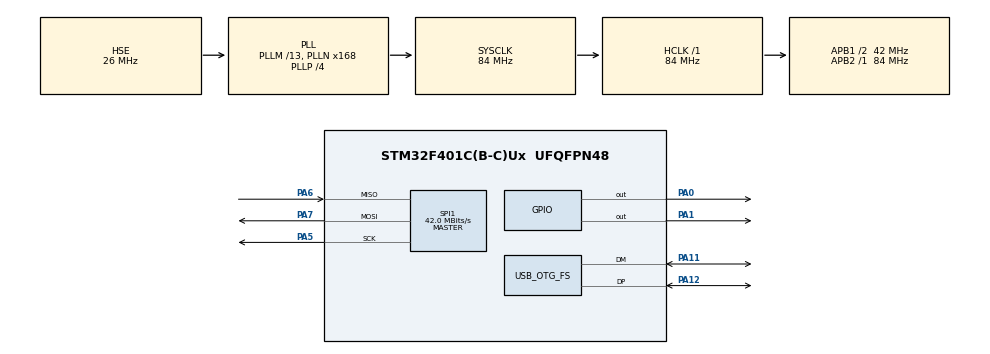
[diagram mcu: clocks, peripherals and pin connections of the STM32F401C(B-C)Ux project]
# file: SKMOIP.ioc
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Mcu.Family=STM32F4
Mcu.Name=STM32F401C(B-C)Ux
Mcu.Package=UFQFPN48
NVIC.OTG_FS_IRQn=true\:0\:0\:false\:false\:true\:false\:true\:true
NVIC.PriorityGroup=NVIC_PRIORITYGROUP_4
PA0-WKUP.Signal=GPIO_Output
PA1.Signal=GPIO_Output
PA11.Mode=Device_Only
PA11.Signal=USB_OTG_FS_DM
PA12.Mode=Device_Only
PA12.Signal=USB_OTG_FS_DP
PA13.Mode=Serial_Wire
PA13.Signal=SYS_JTMS-SWDIO
PA14.Mode=Serial_Wire
PA14.Signal=SYS_JTCK-SWCLK
PA5.Mode=Full_Duplex_Master
PA5.Signal=SPI1_SCK
PA6.Mode=Full_Duplex_Master
PA6.Signal=SPI1_MISO
PA7.Mode=Full_Duplex_Master
PA7.Signal=SPI1_MOSI
PH0\ -\ OSC_IN.Mode=HSE-External-Oscillator
PH0\ -\ OSC_IN.Signal=RCC_OSC_IN
PH1\ -\ OSC_OUT.Mode=HSE-External-Oscillator
PH1\ -\ OSC_OUT.Signal=RCC_OSC_OUT
ProjectManager.HeapSize=0x200
ProjectManager.StackSize=0x400
ProjectManager.TargetToolchain=STM32CubeIDE
RCC.48MHZClocksFreq_Value=48000000
RCC.AHBFreq_Value=84000000
RCC.APB1CLKDivider=RCC_HCLK_DIV2
RCC.APB1Freq_Value=42000000
RCC.APB1TimFreq_Value=84000000
RCC.APB2Freq_Value=84000000
RCC.APB2TimFreq_Value=84000000
RCC.CortexFreq_Value=84000000
RCC.HCLKFreq_Value=84000000
RCC.HSE_VALUE=26000000
RCC.HSI_VALUE=16000000
RCC.LSE_VALUE=32768
RCC.PLLM=13
RCC.PLLN=168
RCC.PLLP=RCC_PLLP_DIV4
RCC.PLLQ=7
RCC.SYSCLKFreq_VALUE=84000000
RCC.SYSCLKSource=RCC_SYSCLKSOURCE_PLLCLK
RCC.VCOOutputFreq_Value=336000000
SPI1.BaudRatePrescaler=SPI_BAUDRATEPRESCALER_2
SPI1.CalculateBaudRate=42.0 MBits/s
SPI1.Direction=SPI_DIRECTION_2LINES
SPI1.Mode=SPI_MODE_MASTER
SPI1.VirtualType=VM_MASTER
USB_DEVICE.CLASS_NAME_FS=HID
USB_DEVICE.VirtualMode=Hid
USB_DEVICE.VirtualModeFS=Hid_FS
USB_OTG_FS.VirtualMode=Device_Only
VP_USB_DEVICE_VS_USB_DEVICE_HID_FS.Mode=HID_FS
board=custom

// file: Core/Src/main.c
/* USER CODE BEGIN Header */
/**
  ******************************************************************************
  * @file           : main.c
  * @brief          : Main program body
  ******************************************************************************
  * @attention
  *
  * Copyright (c) 2023 STMicroelectronics.
  * All rights reserved.
  *
  * This software is licensed under terms that can be found in the LICENSE file
  * in the root directory of this software component.
  * If no LICENSE file comes with this software, it is provided AS-IS.
  *
  ******************************************************************************
  */
/* USER CODE END Header */
#include "main.h"
#include "usb_device.h"
#include "usbd_hid.h"
#include "w5500_spi.h"
#include "wizchip_conf.h"
#include "w5500.h"
#include "socket.h"
#include <stdbool.h>

/* USER CODE BEGIN PTD */

typedef uint8_t u8;
typedef int16_t s16;

/* 12 Bytes */
typedef struct NetworkPacket
{
	/* 1 Byte */
	u8 deviceType;

	union
	{
		/* Keyboard: 3 Bytes */
		struct
		{
			u8 keyStatus;
			u8 usbHIDUsageID;
			u8 modifierKeys;
		};

		/* Mouse: 9 Bytes */
		struct
		{
			/* BIT8(0) = left button is being pressed
			 * BIT8(1) = right button is being pressed
			 * BIT8(2) = middle button is being pressed */
			u8 mouseButtons;
			/* 8 Bytes */
			s16 mousePointX;
			s16 mousePointY;
			s16 mouseWheelX;
			s16 mouseWheelY;
		};

		/* Front Panel: 1 Byte */
		struct
		{
			u8 buttonStatus : 1;
			u8 isPowerButton : 1;
			u8 isResetButton : 1;
		};
	};
} NetworkPacket;

#define RECEIVE_BUFFER_SIZE (1 * sizeof(NetworkPacket)) // must be greater than or equal to 3
#define SEND_KEYBOARD_REPORT_INTERVAL 5
#define SEND_MOUSE_REPORT_INTERVAL 4
#define POWER_STATUS_READ_DELAY 500
#define FRONT_PANEL_POWER_PIN GPIO_PIN_0
#define FRONT_PANEL_RESET_PIN GPIO_PIN_1
#define FRONT_PANEL_POWER_LED_PIN GPIO_PIN_2

typedef enum input_type_t
{
	INPUT_TYPE_KEYBOARD = 0x00,
	INPUT_TYPE_MOUSE = 0x01,
} input_type_t;

typedef enum keycode_t
{
	KEYCODE_A = 4,
	KEYCODE_B,
	KEYCODE_C,
	KEYCODE_D,
	KEYCODE_E,
	KEYCODE_F,
	KEYCODE_G,
	KEYCODE_H,
	KEYCODE_I,
	KEYCODE_J,
	KEYCODE_K,
	KEYCODE_L,
	KEYCODE_M,
	KEYCODE_N,
	KEYCODE_O,
	KEYCODE_P,
	KEYCODE_Q,
	KEYCODE_R,
	KEYCODE_S,
	KEYCODE_T,
	KEYCODE_U,
	KEYCODE_V,
	KEYCODE_W,
	KEYCODE_X,
	KEYCODE_Y,
	KEYCODE_Z,
	KEYCODE_1,
	KEYCODE_2,
	KEYCODE_3,
	KEYCODE_4,
	KEYCODE_5,
	KEYCODE_6,
	KEYCODE_7,
	KEYCODE_8,
	KEYCODE_9,
	KEYCODE_0,
	KEYCODE_RETURN,
	KEYCODE_ESCAPE,
	KEYCODE_DELETEDOT,
	KEYCODE_TAB,
	KEYCODE_SPACEBAR,
	KEYCODE_MINUS,
	KEYCODE_EQUAL,
	KEYCODE_BRACKETSTART,
	KEYCODE_BRACKETEND,
	KEYCODE_BACKSLASH,
	KEYCODE_TILDE,
	KEYCODE_SEMICOLON,
	KEYCODE_SINGLEQUOTE,
	KEYCODE_TILDE2,
	KEYCODE_COMMA,
	KEYCODE_FULLSTOP,
	KEYCODE_FORWARDSLASH,
	KEYCODE_CAPSLOCK,
	KEYCODE_F1,
	KEYCODE_F2,
	KEYCODE_F3,
	KEYCODE_F4,
	KEYCODE_F5,
	KEYCODE_F6,
	KEYCODE_F7,
	KEYCODE_F8,
	KEYCODE_F9,
	KEYCODE_F10,
	KEYCODE_F11,
	KEYCODE_F12,
	KEYCODE_PRINTSCREEN,
	KEYCODE_SCROLLLOCK,
	KEYCODE_PAUSE,
	KEYCODE_INSERT,
	KEYCODE_HOME,
	KEYCODE_PAGEUP,
	KEYCODE_DELETE,
	KEYCODE_END,
	KEYCODE_PAGEDOWN,
	KEYCODE_RIGHTARROW,
	KEYCODE_LEFTARROW,
	KEYCODE_UPARROW,
	KEYCODE_KEYPADNUMLOCK,
	KEYCODE_KEYPADFORWARDSLASH,
	KEYCODE_KEYPADPLUS,
	KEYCODE_KEYPADMINUS,
	KEYCODE_KEYPADENTER,
	KEYCODE_KEYPAD1END,
	KEYCODE_KEYPAD2DOWNARROW,
	KEYCODE_KEYPAD3PAGEDOWN,
	KEYCODE_KEYPAD4LEFTARROW,
	KEYCODE_KEYPAD5,
	KEYCODE_KEYPAD6RIGHTARROW,
	KEYCODE_KEYPAD7HOME,
	KEYCODE_KEYPAD8UPARROW,
	KEYCODE_KEYPAD9PAGEUP,
	KEYCODE_KEYPAD0INSERT,
	KEYCODE_KEYPADDOTDELETE,
	KEYCODE_BACKSLASHBAR,
	KEYCODE_APPLICATION,
	KEYCODE_POWER,
	KEYCODE_KEYPADEQUAL,
	KEYCODE_MAX
} keycode_t;
/* USER CODE END PTD */

SPI_HandleTypeDef hspi1;
extern USBD_HandleTypeDef hUsbDeviceFS;

void SystemClock_Config(void);
static void MX_GPIO_Init(void);
static void MX_SPI1_Init(void);

/* USER CODE BEGIN 0 */

static wiz_NetInfo netInfo =
{
		.mac = { 0xec, 0xec, 0xec, 0xec, 0xec, 0xec },
		.ip = { 192, 168, 1, 117 },
		.sn  = { 255, 255, 255, 0 },
		.gw = { 192, 168, 1, 1 },
		.dns = { 0, 0, 0, 0 },
		.dhcp = NETINFO_STATIC
};

static uint8_t getKeyCodeFromASCII(char ch)
{
	switch(ch)
	{
	case 'a': return KEYCODE_A;
	case 'b': return KEYCODE_B;
	case 'c': return KEYCODE_C;
	case 'd': return KEYCODE_D;
	case 'e': return KEYCODE_E;
	case 'f': return KEYCODE_F;
	case 'g': return KEYCODE_G;
	case 'h': return KEYCODE_H;
	case 'i': return KEYCODE_I;
	case 'j': return KEYCODE_J;
	case 'k': return KEYCODE_K;
	case 'l': return KEYCODE_L;
	case 'm': return KEYCODE_M;
	case 'n': return KEYCODE_N;
	case 'o': return KEYCODE_O;
	case 'p': return KEYCODE_P;
	case 'q': return KEYCODE_Q;
	case 'r': return KEYCODE_R;
	case 's': return KEYCODE_S;
	case 't': return KEYCODE_T;
	case 'u': return KEYCODE_U;
	case 'v': return KEYCODE_V;
	case 'w': return KEYCODE_W;
	case 'x': return KEYCODE_X;
	case 'y': return KEYCODE_Y;
	case 'z': return KEYCODE_Z;
	case '1': return KEYCODE_1;
	case '2': return KEYCODE_2;
	case '3': return KEYCODE_3;
	case '4': return KEYCODE_4;
	case '5': return KEYCODE_5;
	case '6': return KEYCODE_6;
	case '7': return KEYCODE_7;
	case '8': return KEYCODE_8;
	case '9': return KEYCODE_9;
	case '0': return KEYCODE_0;
	case '\n': return KEYCODE_RETURN;
	case '\r': return KEYCODE_RETURN;
	case '\b': return KEYCODE_DELETEDOT;
	case '\t': return KEYCODE_TAB;
	case ' ': return KEYCODE_SPACEBAR;
	default: return 0;
	}
	return 0;
}

static void SetupNetworkDevice()
{
	wizchip_setnetinfo(&netInfo);
	ctlnetwork(CN_SET_NETINFO, &netInfo);
}

static char getCode(int32_t size)
{
	switch(size)
	{
	case SOCKERR_SOCKSTATUS: return 'd';
	case SOCKERR_SOCKMODE: return 'e';
	case SOCKERR_SOCKNUM: return 'f';
	case SOCKERR_DATALEN: return 'g';
	case SOCK_BUSY: return 'h';
	default: return 'i';
	}
}

struct
{
	  uint8_t reportID;
	  uint8_t modifier;
	  uint8_t reserved;
	  uint8_t keycode0;
	  uint8_t keycode1;
	  uint8_t keycode2;
	  uint8_t keycode3;
	  uint8_t keycode4;
	  uint8_t keycode5;
} keyboardReport = { 0x01 };

struct
{
	  uint8_t reportID;
	  uint8_t button;
	  int8_t mouse_x;
	  int8_t mouse_y;
	  int8_t wheel;
} mouseReport = { 0x02 };

typedef enum key_status_t
{
	KEY_STATUS_RELEASED = 0,
	KEY_STATUS_PRESSED
} key_status_t;

static inline void SendKeyboardReportASCII(uint8_t keycode)
{
	keyboardReport.keycode0 = getKeyCodeFromASCII((char)keycode);
	USBD_HID_SendReport(&hUsbDeviceFS, (uint8_t*)&keyboardReport, sizeof(keyboardReport));
	keyboardReport.keycode0 = 0;
	HAL_Delay(10);
	USBD_HID_SendReport(&hUsbDeviceFS, (uint8_t*)&keyboardReport, sizeof(keyboardReport));
	HAL_Delay(20);
}

static __attribute__((always_inline)) inline void SendKeyboardReport(uint8_t hidUsageID, uint8_t modifierKeys, key_status_t status)
{
	keyboardReport.modifier = modifierKeys;
	switch(status)
	{
		case KEY_STATUS_RELEASED:
			{
				keyboardReport.keycode0 = 0;
				break;
			}
		case KEY_STATUS_PRESSED:
			{
				keyboardReport.keycode0 = hidUsageID;
				break;
			}
		default: { return; }
	}
	USBD_HID_SendReport(&hUsbDeviceFS, (uint8_t*)&keyboardReport, sizeof(keyboardReport));
}

static __attribute__((always_inline)) inline void SendMouseReport(uint8_t button, int8_t dx, int8_t dy, int8_t wheel)
{
	mouseReport.button = button;
	mouseReport.mouse_x = dx;
	mouseReport.mouse_y = dy;
	mouseReport.wheel = wheel;
	USBD_HID_SendReport(&hUsbDeviceFS, (uint8_t*)&mouseReport, sizeof(mouseReport));
}

static inline void Info(const char* str)
{
	uint8_t len = strlen(str);
	for(uint8_t i = 0; i < len; i++)
		 SendKeyboardReportASCII(str[i]);
}

static inline void Error(const char* str)
{
	Info("Error: ");
	Info(str);
	while(1);
}

/* USER CODE END 0 */

int main(void)
{

  /* MCU Configuration--------------------------------------------------------*/

  /* Reset of all peripherals, Initializes the Flash interface and the Systick. */
  HAL_Init();

  /* Configure the system clock */
  SystemClock_Config();

  /* Initialize all configured peripherals */
  MX_GPIO_Init();
  MX_SPI1_Init();
  MX_USB_DEVICE_Init();
  /* USER CODE BEGIN 2 */
CREATE_SOCKET:
  W5500_Init();
  SetupNetworkDevice();
  SOCKET mySocket = socket(0, Sn_MR_TCP, 2000, 0);

  if(mySocket != 0)
  {
	  Error("failed to create socket 0\n");
  }

  if(sizeof(NetworkPacket) != 12)
  {
  	Error("sizeof network packet incorrect");
  }

  uint8_t recieveBuffer[RECEIVE_BUFFER_SIZE];

  /* USER CODE END 2 */

  /* Infinite loop */
  /* USER CODE BEGIN WHILE */
  while (1)
  {
LISTEN_AGAIN:
	  if(listen(mySocket) != SOCK_OK)
	  {
		  goto CREATE_SOCKET;
	  }

	  while(getSn_SR(mySocket) != SOCK_ESTABLISHED);

	  while(1)
	  {
		  int32_t size = recv(mySocket, recieveBuffer, RECEIVE_BUFFER_SIZE);
		  if(size <= 0)
		  {
			  if(size == SOCKERR_SOCKSTATUS)
			  {
				  if(close(mySocket) != SOCK_OK)
					  goto LISTEN_AGAIN;
				  HAL_Delay(100);
				  if(socket(mySocket, Sn_MR_TCP, 2000, 0) != mySocket)
				  {
				  	  goto LISTEN_AGAIN;
				  }
				  break;
			  }
			  continue;
		  }

		  NetworkPacket* packet = (NetworkPacket*)(recieveBuffer);
		  switch(packet->deviceType)
		  {
		  	  case 1 /* Mouse */:
		  	  {
			  	SendMouseReport(packet->mouseButtons, (int8_t)(packet->mousePointX), (int8_t)(packet->mousePointY), (int8_t)packet->mouseWheelX);
		  		break;
		  	  }
		  	  case 0 /* Keyboard */:
			  {
				SendKeyboardReport(packet->usbHIDUsageID, packet->modifierKeys, (key_status_t)packet->keyStatus);
				break;
			  }
		  	  case 2: /* Front Pane */
		  	  {
		  		if(packet->isPowerButton || packet->isResetButton)
		  		{
		  			if(packet->isPowerButton)
		  			{
		  				switch(packet->buttonStatus)
		  				{
		  					case 0:
		  					{
		  						HAL_GPIO_WritePin(GPIOA, FRONT_PANEL_POWER_PIN, GPIO_PIN_RESET);
		  						break;
		  					}
		  					case 1:
		  					{
		  						HAL_GPIO_WritePin(GPIOA, FRONT_PANEL_POWER_PIN, GPIO_PIN_SET);
		  						break;
		  					}
		  				}
		  			}
		  			else /* if(packet->isResetButton) */
		  			{
		  				switch(packet->buttonStatus)
		  				{
		  					case 0:
		  					{
		  						HAL_GPIO_WritePin(GPIOA, FRONT_PANEL_RESET_PIN, GPIO_PIN_RESET);
		  						break;
		  					}
		  					case 1:
		  					{
		  						HAL_GPIO_WritePin(GPIOA, FRONT_PANEL_RESET_PIN, GPIO_PIN_SET);
		  						break;
		  					}
		  				}
		  			}
		  		}
		  		break;
		  	  }
		  	  case 3:
		  	  {
		  		  HAL_Delay(POWER_STATUS_READ_DELAY);
		  		  GPIO_PinState state = HAL_GPIO_ReadPin(GPIOA, FRONT_PANEL_POWER_LED_PIN);
		  		  int32_t result = send(mySocket, &state, sizeof(state));
				  if(result <= 0)
				  {
					  if(result == SOCKERR_SOCKSTATUS)
					  {
						  if(close(mySocket) != SOCK_OK)
							  goto LISTEN_AGAIN;
						  HAL_Delay(100);
						  if(socket(mySocket, Sn_MR_TCP, 2000, 0) != mySocket)
						  {
						  	  goto LISTEN_AGAIN;
						  }
					  }
					  goto LISTEN_AGAIN;
				  }
		  		  break;
		  	  }
		  }
	  }
  }
  /* USER CODE END WHILE */

  /* USER CODE BEGIN 3 */
  close(mySocket);
  /* USER CODE END 3 */
}

void SystemClock_Config(void)
{
  RCC_OscInitTypeDef RCC_OscInitStruct = {0};
  RCC_ClkInitTypeDef RCC_ClkInitStruct = {0};

  /** Configure the main internal regulator output voltage
  */
  __HAL_RCC_PWR_CLK_ENABLE();
  __HAL_PWR_VOLTAGESCALING_CONFIG(PWR_REGULATOR_VOLTAGE_SCALE2);

  /** Initializes the RCC Oscillators according to the specified parameters
  * in the RCC_OscInitTypeDef structure.
  */
  RCC_OscInitStruct.OscillatorType = RCC_OSCILLATORTYPE_HSE;
  RCC_OscInitStruct.HSEState = RCC_HSE_ON;
  RCC_OscInitStruct.PLL.PLLState = RCC_PLL_ON;
  RCC_OscInitStruct.PLL.PLLSource = RCC_PLLSOURCE_HSE;
  RCC_OscInitStruct.PLL.PLLM = 13;
  RCC_OscInitStruct.PLL.PLLN = 168;
  RCC_OscInitStruct.PLL.PLLP = RCC_PLLP_DIV4;
  RCC_OscInitStruct.PLL.PLLQ = 7;
  if (HAL_RCC_OscConfig(&RCC_OscInitStruct) != HAL_OK)
  {
    Error_Handler();
  }

  /** Initializes the CPU, AHB and APB buses clocks
  */
  RCC_ClkInitStruct.ClockType = RCC_CLOCKTYPE_HCLK|RCC_CLOCKTYPE_SYSCLK
                              |RCC_CLOCKTYPE_PCLK1|RCC_CLOCKTYPE_PCLK2;
  RCC_ClkInitStruct.SYSCLKSource = RCC_SYSCLKSOURCE_PLLCLK;
  RCC_ClkInitStruct.AHBCLKDivider = RCC_SYSCLK_DIV1;
  RCC_ClkInitStruct.APB1CLKDivider = RCC_HCLK_DIV2;
  RCC_ClkInitStruct.APB2CLKDivider = RCC_HCLK_DIV1;

  if (HAL_RCC_ClockConfig(&RCC_ClkInitStruct, FLASH_LATENCY_2) != HAL_OK)
  {
    Error_Handler();
  }
}

static void MX_SPI1_Init(void)
{

  /* SPI1 parameter configuration*/
  hspi1.Instance = SPI1;
  hspi1.Init.Mode = SPI_MODE_MASTER;
  hspi1.Init.Direction = SPI_DIRECTION_2LINES;
  hspi1.Init.DataSize = SPI_DATASIZE_8BIT;
  hspi1.Init.CLKPolarity = SPI_POLARITY_LOW;
  hspi1.Init.CLKPhase = SPI_PHASE_1EDGE;
  hspi1.Init.NSS = SPI_NSS_SOFT;
  hspi1.Init.BaudRatePrescaler = SPI_BAUDRATEPRESCALER_2;
  hspi1.Init.FirstBit = SPI_FIRSTBIT_MSB;
  hspi1.Init.TIMode = SPI_TIMODE_DISABLE;
  hspi1.Init.CRCCalculation = SPI_CRCCALCULATION_DISABLE;
  hspi1.Init.CRCPolynomial = 10;
  if (HAL_SPI_Init(&hspi1) != HAL_OK)
  {
    Error_Handler();
  }

}

static void MX_GPIO_Init(void)
{
  GPIO_InitTypeDef GPIO_InitStruct = {0};

  /* GPIO Ports Clock Enable */
  __HAL_RCC_GPIOH_CLK_ENABLE();
  __HAL_RCC_GPIOA_CLK_ENABLE();

  /*Configure GPIO pin Output Level */
  HAL_GPIO_WritePin(GPIOA, GPIO_PIN_3|GPIO_PIN_4, GPIO_PIN_RESET);

  /*Configure GPIO pins : PA0 PA1 */
  GPIO_InitStruct.Pin = GPIO_PIN_3|GPIO_PIN_4;
  GPIO_InitStruct.Mode = GPIO_MODE_OUTPUT_PP;
  GPIO_InitStruct.Pull = GPIO_NOPULL;
  GPIO_InitStruct.Speed = GPIO_SPEED_FREQ_LOW;
  HAL_GPIO_Init(GPIOA, &GPIO_InitStruct);

/* USER CODE BEGIN MX_GPIO_Init_2 */
  HAL_GPIO_WritePin(GPIOA, FRONT_PANEL_POWER_PIN | FRONT_PANEL_RESET_PIN, GPIO_PIN_RESET);
  GPIO_InitStruct.Pin = FRONT_PANEL_POWER_PIN | FRONT_PANEL_RESET_PIN;
  GPIO_InitStruct.Mode = GPIO_MODE_OUTPUT_PP;
  GPIO_InitStruct.Pull = GPIO_PULLDOWN;
  GPIO_InitStruct.Speed = GPIO_SPEED_FREQ_LOW;
  HAL_GPIO_Init(GPIOA, &GPIO_InitStruct);

  GPIO_InitStruct.Pin = FRONT_PANEL_POWER_LED_PIN;
  GPIO_InitStruct.Mode = GPIO_MODE_INPUT;
  GPIO_InitStruct.Pull = GPIO_PULLDOWN;
  GPIO_InitStruct.Speed = GPIO_SPEED_FREQ_LOW;
  HAL_GPIO_Init(GPIOA, &GPIO_InitStruct);

/* USER CODE END MX_GPIO_Init_2 */
}

void Error_Handler(void)
{
  __disable_irq();
  while (1)
  {
  }
}
